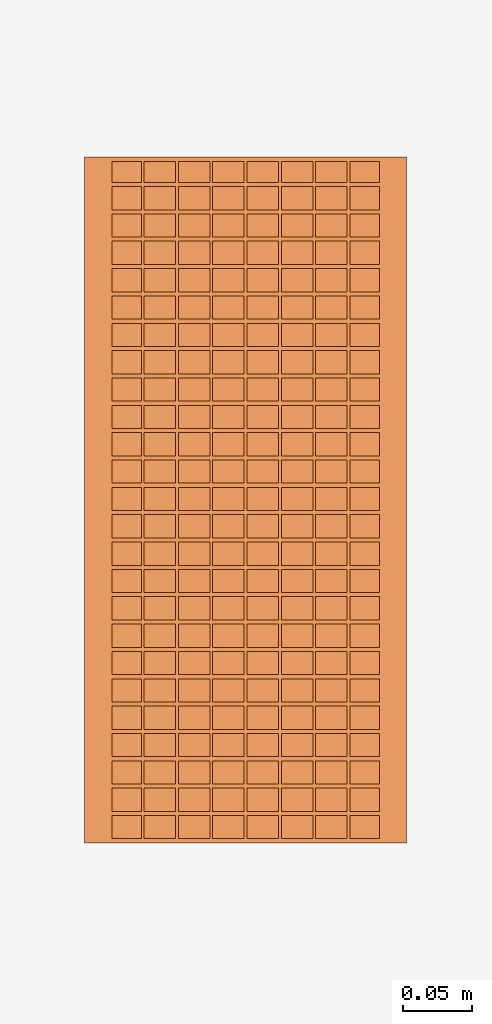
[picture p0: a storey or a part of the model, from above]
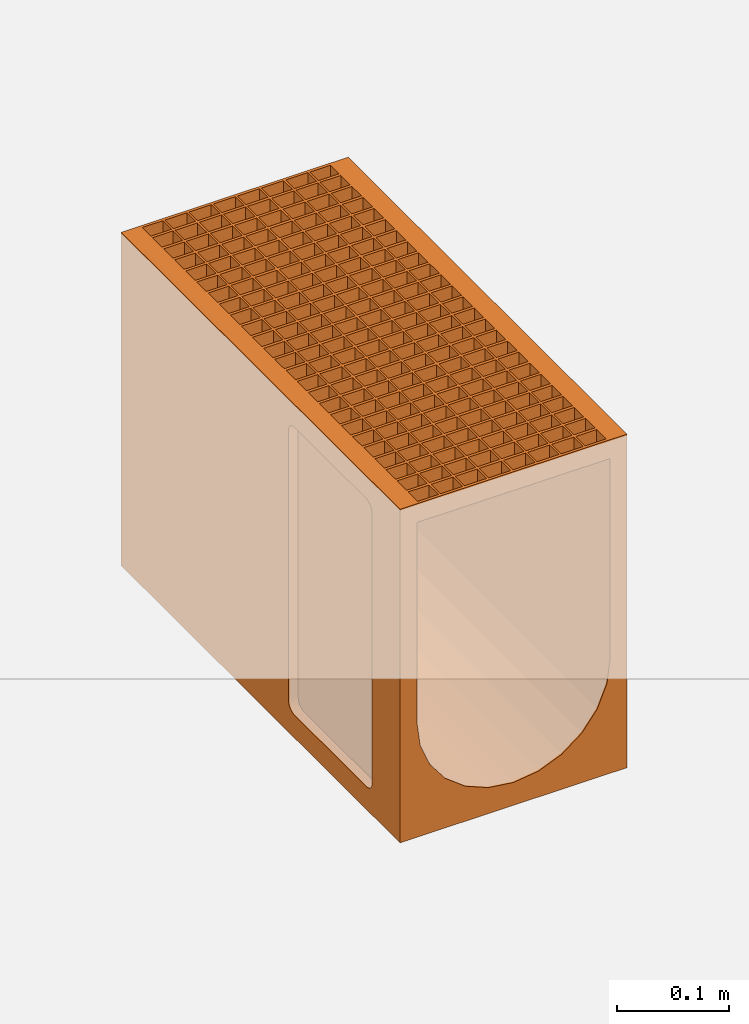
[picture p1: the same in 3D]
Properties of the parts of a building model (IFC2X3)

# File
Description: ViewDefinition [CoordinationView]
File name: 24215 - No 20.1J Constant Depth Channel - 500mm LG - Invert Depth 340mm.ifc
Time: 2013-10-16T12:50:21
Written by: Autodesk Revit 2013
Made in: 20120221_2030(x64)

# IfcProject, Project Number
LongName: Project Name; Phase: Project Status

# IfcSite, Default
RefLatitude: 42, 21, 30, 344238; RefLongitude: -71, -3, -35, -194702; RefElevation: 0 mm

# IfcBuilding
Pset_BuildingCommon - NumberOfStoreys: 1
Other - Client Name: Owner; Project Number: Project Number; Project Issue Date: Issue Date; Project Status: Project Status; Project Name: Project Name; Project Address: ## Street City, State Zip

# IfcBuildingStorey, Level 1
LongName: Level 1; Elevation: 0 mm
Constraints - Elevation Base: 0; Elevation: 0 mm
Graphics - Symbol at End 2 Default: yes; Line Pattern: Center; Symbol at End 1 Default: no; Symbol: M_Level Head - Circle: M_Level Head - Circle; Line Weight: 1; Color: 0
Identity Data - Name: Level 1; Building Story: yes; Structural: no
Dimensions - Computation Height: 0 mm

# IfcBuildingElementProxy: 24215 - No 20.1J Constant Depth Channel - 500mm LG - Invert Depth 340mm, Civil-Drainage-Channel-ACO-MultiDrain-M200DS-Channel-System:24215 - No 20.1J Constant Depth Channel - 500mm LG - Invert Depth 340mm:24215 - No 20.1J Constant Depth Channel - 500mm LG - Invert Depth 340mm:1152340
In: Level 1
Material: Vienite® Synthetic Resin Concrete
Dimensions - Custom_Value_Length: 0 mm; Length: 1000 mm; FloorCut_Length: -500 mm; EndCap Position: 500 mm; Volume: 10396112 mm3; FloorCut_Depth: 365 mm; EndCap_Height: 365 mm; InvDepth: 240 mm; FloorCut_HorPosition: 117.5 mm; Depth: 365 mm; FloorCut_Width: 235 mm
Construction - 23219 - Universal Endcap (Female End): no; 13449 - Grating - Mesh - Stainless Steel - 500mm Long: no; 23219 - Universal Endcap (Male End): no; 13448 - Grating - Mesh - Stainless Steel - 1000mm Long: no; 23410_Sump Unit: no; Constant Depth Channel_500: yes; Grating_1000mm: no; Shallow Depth Channel: no; Constant Depth Channel_1000: no; Grating_500mm: yes; Shallow Depth Channel with seal: no
Phasing - Phase Created: New Construction
Constraints - Moves With Nearby Elements: no; Level: Level: Level 1
Pset_BuildingElementProxyCommon - Reference: 24215 - No 20.1J Constant Depth Channel - 500mm LG - Invert Depth 340mm
Model Properties - Grating Product code 13449: Load Class C250 - Mesh Stainless Steel Grade 304 13449DL 500mm long - 23x17mm slot - Intake area 154100mm²/m - 6.0kg; Grating Product code 13448: N/A; End Cap Product code 23219: No 306 Universal End Cap - 235mm wide x 365mm long - Spigot Ø160mm x 75mm long - Silver - Polypropylene - 0.4kg
Identity Data - Fax: +44 (0)1462 815895; Model Description: Channel drainage system; Watermarked With: BIM Manager Premium Suite; Watermark 2: This file is water marked and users are prohibited to reproduce, adapt, distribute this information; Product Page URL: http://www.aco.co.uk/product_detail.php?id=15; Assembly Code: D2040; Maintenance guidelines: http://www.aco.co.uk/download.php?id=173; OmniClass Number: 23.70.50.24; OmniClass Title: Rainwater Removal; Manufacturer: ACO Technologies plc - ACO Water Management Division; Watermarked By: www.aco.co.uk; Telephone: +44 (0)1462 816666; Product Code: 24215; Type Comments: ACO MultiDrain M200DS 20.1J Constant Depth Channel 500mm Long; Assembly Description: Rain Water Drainage; Cost: 0; Model: ACO MultiDrain MD - M200DS; e-mail Technical: technical@aco.co.uk; Price: POA - contact ACO; Watermark 1: This file is the property of ACO Technologies PLC; e-mail Sales: customersupport@aco.co.uk; Address: ACO Business Park, Hitchin Road, Shefford, Bedfordshire, United Kingdom SG17 5TE; Installation guidelines: http://www.aco.co.uk/download.php?id=173; Product brochure: http://www.aco.co.uk/download.php?id=173; URL: www.aco.co.uk
Green Building Properties - Channel Recycled Material Content: 20% minimum; Channel Recyclable: Fully recyclable; Edge Rail Recycled Material Content: Between 40% - 90%; Edge Rail Recyclable: Fully recyclable
General - SerialNumber: 0; TagNumber: 0
Materials and Finishes - Channel Material: Vienite® Synthetic Resin Concrete; Edge Rail Material: Stainless Steel Grade 304; Edge Rail Colour: Self; Channel Colour: Brown
Data - Load Class: A 15 - D 400; Installation - Concrete Grade: Refer to brochure; Concrete Surround Volume - Load Class B 125 - C 250 - Concrete Pavement: 0.20m³/m; Product Weight: 22.9 Kg; Product Dimensions: 500mm x 235mm x 365mm (LxWxH); Concrete Surround Volume - Load Class A 15 - Concrete Pavement: 0.13m³/m; Product Standard: BS EN 1433:2002, CE marked; Invert Depth: 340mm; Channel C.S.A: 0.051m²; ACO Hydraulic Design Software: http://www.acodesign.co.uk; Concrete Surround Volume - Load Class D 400 - Concrete Pavement: 0.29m³/m; Hydraulic Performance: http://www.aco.co.uk/download.php?id=173
Other - Revision: 1; CreatedBy: www.aco.co.uk

# IfcOpeningElement: Recess
In: Level 1
Phasing - Phase Created: New Construction
Dimensions - Area: 25000000 mm2; Perimeter: 20000 mm; Volume: 9957112500 mm3; Thickness: 400 mm
Structural - Structural: no; Enable Analytical Model: no
Constraints - Room Bounding: yes; Level: Level: Level 1; Related to Mass: no; Height Offset From Level: 0 mm
Construction - Default Thickness: 400 mm; Function: 0
Graphics - Coarse Scale Fill Color: 0
Analytical Properties - Thermal Resistance (R): 0.477897; Roughness: 1; Absorptance: 0.1; Heat Transfer Coefficient (U): 2.0925; Thermal mass: 543920
Materials and Finishes - Structural Material: Earth

# IfcSlab: Floor:Generic Floor - 400mm, Floor:Generic Floor - 400mm:193825
In: Level 1
PredefinedType: FLOOR; Material: Earth 400 mm
Phasing - Phase Created: New Construction
Dimensions - Area: 25000000 mm2; Perimeter: 20000 mm; Volume: 9957112500 mm3; Thickness: 400 mm
Structural - Structural: no; Enable Analytical Model: no
Constraints - Room Bounding: yes; Level: Level: Level 1; Related to Mass: no; Height Offset From Level: 0 mm
Pset_SlabCommon - Reference: Generic Floor - 400mm; IsExternal: no; LoadBearing: yes
Construction - Default Thickness: 400 mm; Function: 0
Graphics - Coarse Scale Fill Color: 0
Analytical Properties - Thermal Resistance (R): 0.477897; Roughness: 1; Absorptance: 0.1; Heat Transfer Coefficient (U): 2.0925; Thermal mass: 543920
Materials and Finishes - Structural Material: Earth
